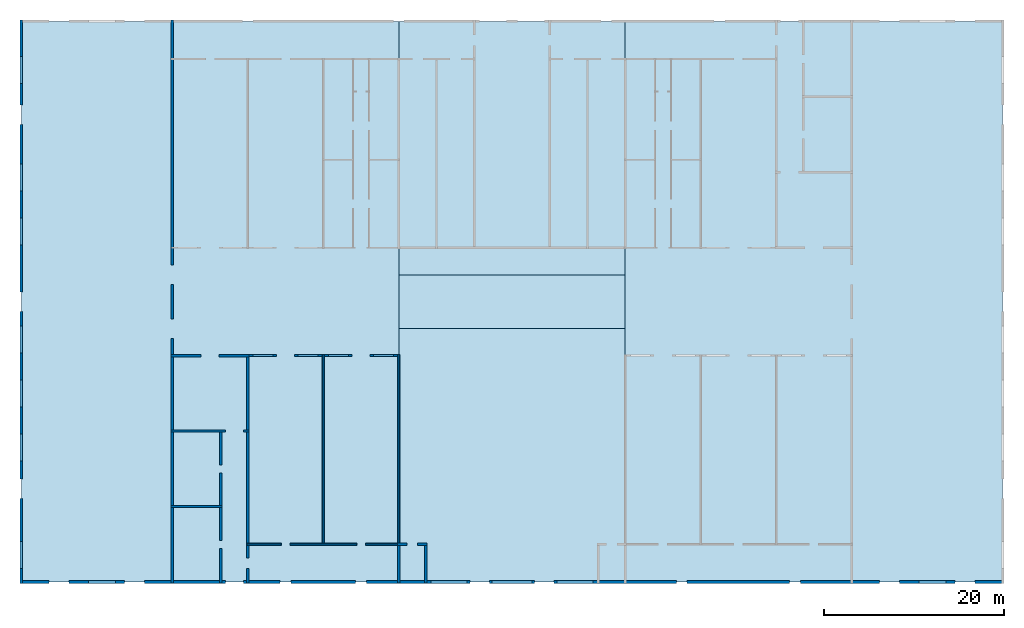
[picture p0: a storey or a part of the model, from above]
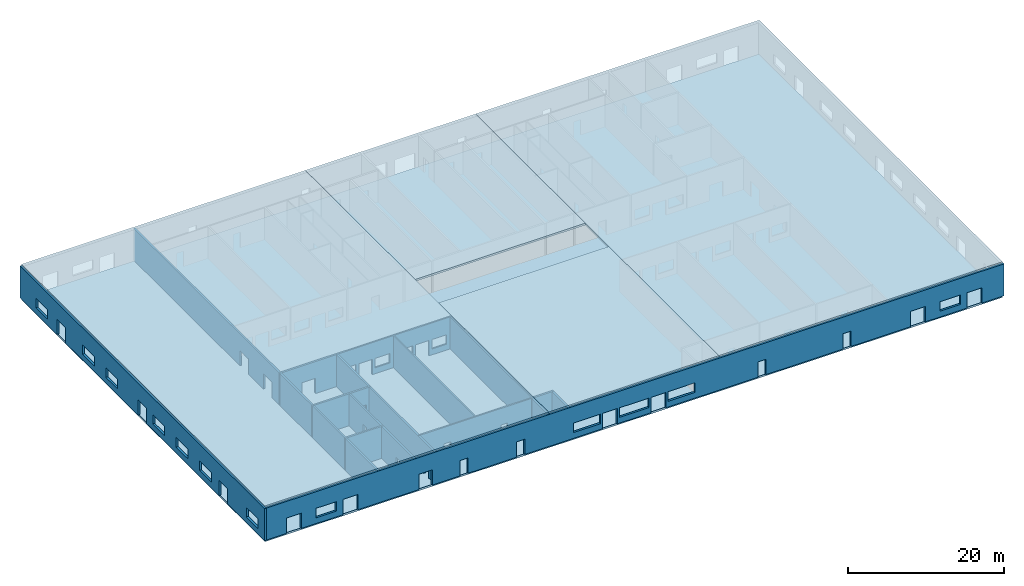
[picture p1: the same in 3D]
Properties of the parts of a building model (IFC4)

# File
Description: ViewDefinition[DesignTransferView]
File name: /dev/null
Time: 2026-10-29T19:15:15+03:00
Written by: IfcOpenShell 0.9.0.post1
Made in: IfcOpenShell 0.9.0.post1
Authorization: Nobody

# IfcBuildingStorey, Ground Floor
In: Sample Shopping Mall
Elevation: 0 mm

# IfcSpace (42)
In: Ground Floor
Name | LongName = Reference
01 | MALL STREET & ATRIUM
02 | LIFTS
03 | LIFTS
04 | ANCHOR STORE W
05 | ANCHOR STORE E
06 | SERVICE CORRIDOR SW1
07 | SERVICE CORRIDOR SE2
08 | SERVICE CORRIDOR NW1
09 | SERVICE CORRIDOR NE2
10 | ESCAPE STAIR 1
11 | PASSAGE 1
12 | ELEC RISER 1
13 | MECH RISER 1
14 | SHOP 01
15 | SHOP 02
16 | SHOP 03
17 | SHOP 04
18 | SHOP 05
19 | SHOP 06
20 | SHOP 07
21 | LINK
22 | ACCESS WC
23 | MEN WC
24 | WOMEN WC
25 | BABY CARE
26 | FIRST AID
27 | MDB
28 | FIRE PUMP
29 | LOADING BAY
30 | AHU PLANT
31 | GEN SET
32 | LINK
33 | ACCESS WC
34 | MEN WC
35 | WOMEN WC
36 | BABY CARE
37 | FIRST AID
38 | SHOP 08
39 | ESCAPE STAIR 2
40 | PASSAGE 2
41 | ELEC RISER 2
42 | MECH RISER 2

# IfcDoor (114)
In: Ground Floor
OverallHeight: 2.4 mm; PredefinedType: DOOR
Name | OverallWidth (mm)
D01 | 1.2
D02 | 1.2
D03 | 1.1
20 x  | 1.1
D04 | 1.1
D05 | 1.1
D06 | 1.1
D07 | 1.1
D08 | 1.1
D09 | 1.1
D10 | 1.1
D11 | 1.1
D12 | 1.1
D13 | 1.1
D14 | 1.1
D15 | 1.1
D16 | 1.1
D17 | 1.1
D18 | 1.1
D19 | 1.1
D20 | 1.1
D21 | 1.1
D22 | 1.1
D23 | 1.2
D24 | 1.2
D25 | 1.2
D26 | 1.2
D27 | 1.2
D28 | 1.2
D29 | 1.2
D30 | 1.2
D31 | 1
32 x  | 1
D32 | 1
D33 | 1
4 x  | 0.9
8 x  | 1.2
D37 | 1
D39 | 1
D41 | 1
D43 | 1
D45 | 1
D47 | 1
D49 | 1
D51 | 1.2
D59 | 1.5
2 x  | 1.5
D60 | 1.5
D65 | 1.2
D71 | 1
D73 | 1
D74 | 1
D75 | 1

# IfcSlab (5)
In: Ground Floor
Name | PredefinedType
Ground slab | FLOOR
Roof slab 0 | ROOF
Roof slab 1 | ROOF
Roof slab 2 | ROOF
Roof slab 3 | ROOF

# IfcWall: WT-150 (10)
In: Ground Floor
Type - PredefinedType: SOLIDWALL
Pset_WallCommon - IsExternal: no; LoadBearing: no
Name
W15
W16
W17
W18
W20
W21
W34
W35
W48
W49

# IfcWall: WT-200 (16)
In: Ground Floor
Type - PredefinedType: SOLIDWALL
Pset_WallCommon - IsExternal: no; LoadBearing: yes
Name
W1
W4
W8
W9
W10
W12
W22
W25
W31
W32
W33
W37
W46
W50
W51
W52

# IfcWall: WT-250 (27)
In: Ground Floor
Type - PredefinedType: SOLIDWALL
Pset_WallCommon - LoadBearing: yes
Name | IsExternal
W2 | no
W3 | no
W5 | no
W6 | no
W7 | no
W11 | no
W13 | no
W14 | no
W19 | no
W23 | no
W24 | no
W28 | yes
W29 | no
W30 | no
W36 | no
W38 | no
W39 | no
W40 | no
W41 | no
W42 | no
W43 | no
W44 | no
W45 | no
W47 | no
W53 | no
W54 | no
W55 | yes

# IfcWall: WT-300 (4)
In: Ground Floor
Type - PredefinedType: SOLIDWALL
Pset_WallCommon - IsExternal: yes; LoadBearing: yes
Name
W0
W26
W27
W56

# IfcWindow (37)
In: Ground Floor
OverallHeight: 1.5 mm; PredefinedType: WINDOW
Name | OverallWidth (mm)
2 x  | 4
 | 4.4
16 x  | 2.2
18 x  | 3
